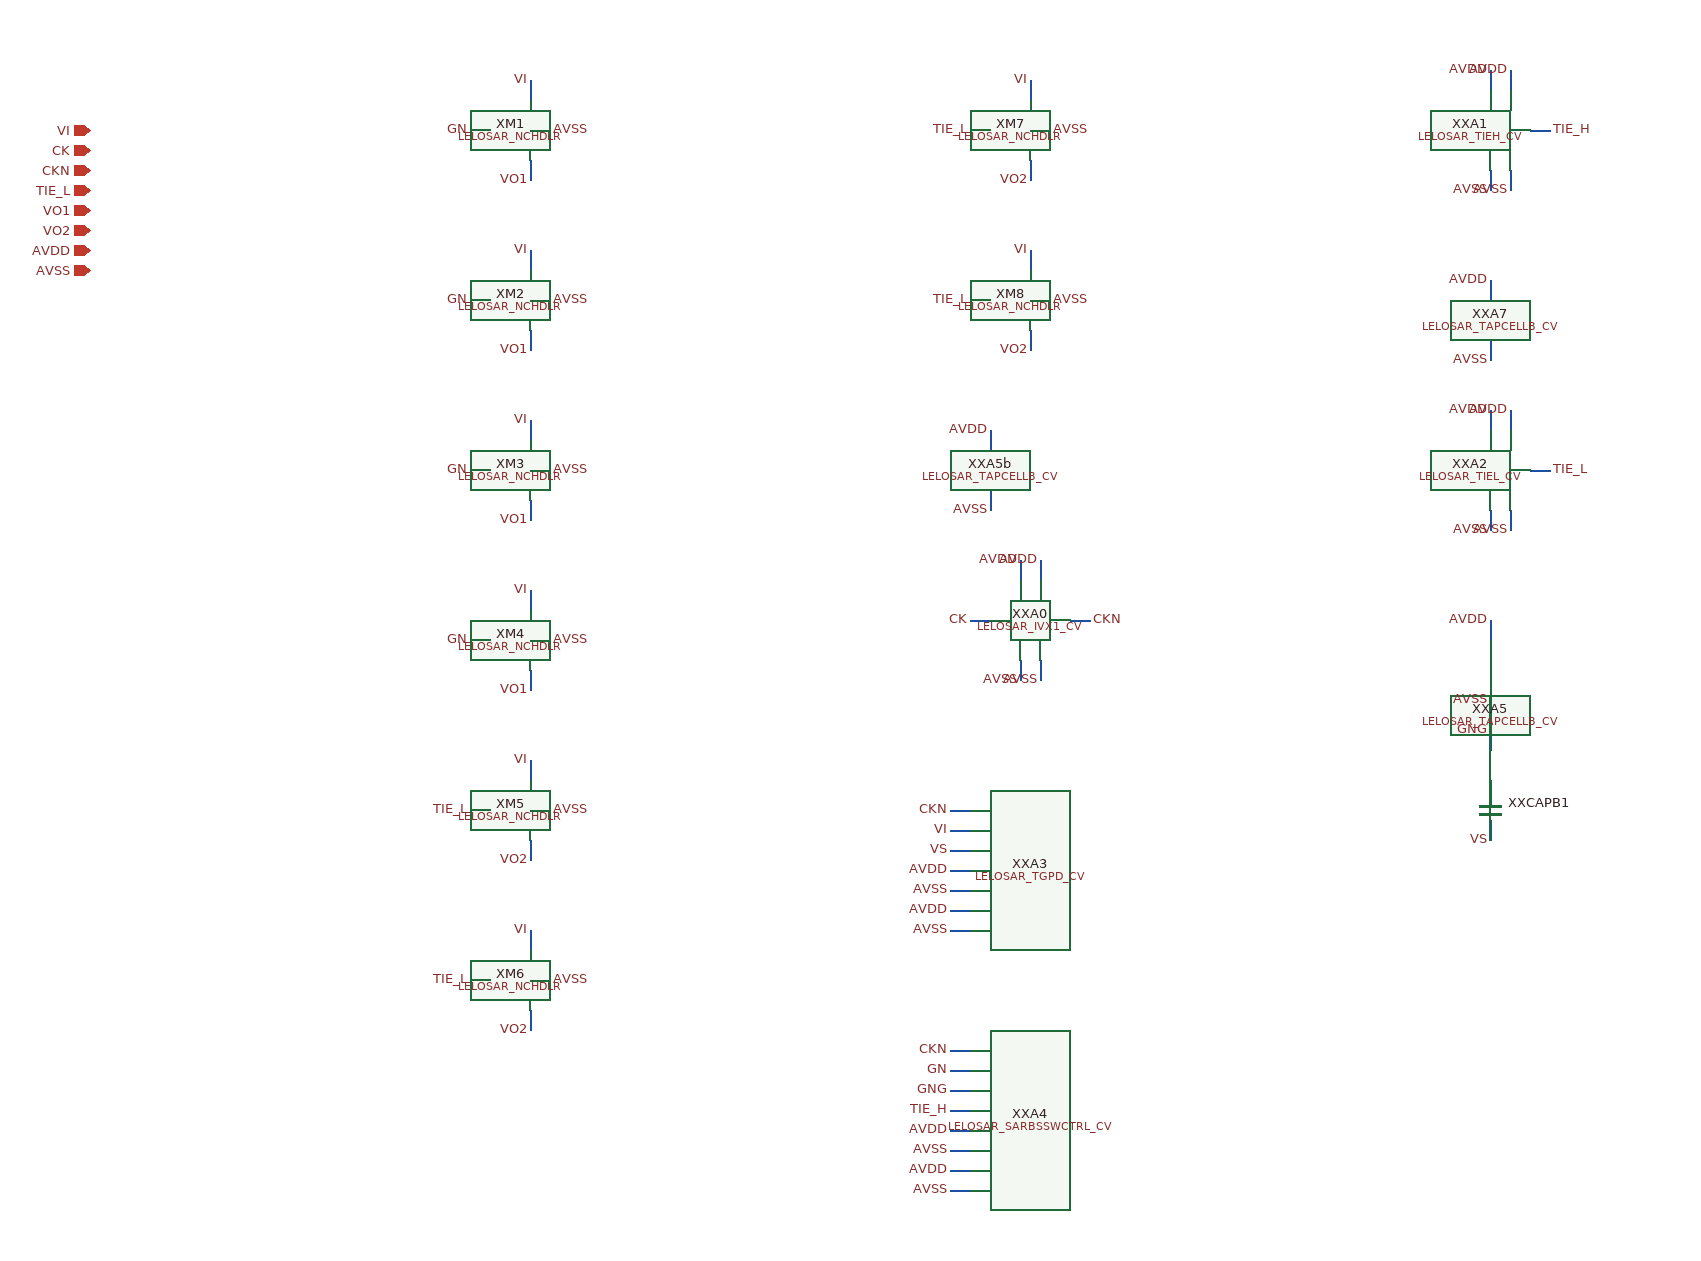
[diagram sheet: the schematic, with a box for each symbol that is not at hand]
v {xschem version=3.0.0 file_version=1.2 }
G {}
K {}
V {}
S {}
E {}
C {devices/iopin.sym} 0 0 0 0 {name=p0 lab=VI}
C {devices/iopin.sym} 0 20 0 0 {name=p1 lab=CK}
C {devices/iopin.sym} 0 40 0 0 {name=p2 lab=CKN}
C {devices/iopin.sym} 0 60 0 0 {name=p3 lab=TIE_L}
C {devices/iopin.sym} 0 80 0 0 {name=p4 lab=VO1}
C {devices/iopin.sym} 0 100 0 0 {name=p5 lab=VO2}
C {devices/iopin.sym} 0 120 0 0 {name=p6 lab=AVDD}
C {devices/iopin.sym} 0 140 0 0 {name=p7 lab=AVSS}
C {LELO_SAR9B_GF180MCUD/LELOSAR_NCHDLR.sym} 400 0 0 0 {name=XM1}
N 440.0 -50.0 440.0 -30.0 {lab=VI}
C {devices/lab_pin.sym} 440.0 -50.0 3 0 {name=l0 sig_type=std_logic lab=VI }
N 380.0 0.0 400.0 0.0 {lab=GN}
C {devices/lab_pin.sym} 380.0 0.0 0 0 {name=l1 sig_type=std_logic lab=GN }
N 440.0 50.0 440.0 30.0 {lab=VO1}
C {devices/lab_pin.sym} 440.0 50.0 1 0 {name=l2 sig_type=std_logic lab=VO1 }
N 460.0 0.0 440.0 0.0 {lab=AVSS}
C {devices/lab_pin.sym} 460.0 0.0 2 0 {name=l3 sig_type=std_logic lab=AVSS }
C {LELO_SAR9B_GF180MCUD/LELOSAR_NCHDLR.sym} 400 170 0 0 {name=XM2}
N 440.0 120.0 440.0 140.0 {lab=VI}
C {devices/lab_pin.sym} 440.0 120.0 3 0 {name=l4 sig_type=std_logic lab=VI }
N 380.0 170.0 400.0 170.0 {lab=GN}
C {devices/lab_pin.sym} 380.0 170.0 0 0 {name=l5 sig_type=std_logic lab=GN }
N 440.0 220.0 440.0 200.0 {lab=VO1}
C {devices/lab_pin.sym} 440.0 220.0 1 0 {name=l6 sig_type=std_logic lab=VO1 }
N 460.0 170.0 440.0 170.0 {lab=AVSS}
C {devices/lab_pin.sym} 460.0 170.0 2 0 {name=l7 sig_type=std_logic lab=AVSS }
C {LELO_SAR9B_GF180MCUD/LELOSAR_NCHDLR.sym} 400 340 0 0 {name=XM3}
N 440.0 290.0 440.0 310.0 {lab=VI}
C {devices/lab_pin.sym} 440.0 290.0 3 0 {name=l8 sig_type=std_logic lab=VI }
N 380.0 340.0 400.0 340.0 {lab=GN}
C {devices/lab_pin.sym} 380.0 340.0 0 0 {name=l9 sig_type=std_logic lab=GN }
N 440.0 390.0 440.0 370.0 {lab=VO1}
C {devices/lab_pin.sym} 440.0 390.0 1 0 {name=l10 sig_type=std_logic lab=VO1 }
N 460.0 340.0 440.0 340.0 {lab=AVSS}
C {devices/lab_pin.sym} 460.0 340.0 2 0 {name=l11 sig_type=std_logic lab=AVSS }
C {LELO_SAR9B_GF180MCUD/LELOSAR_NCHDLR.sym} 400 510 0 0 {name=XM4}
N 440.0 460.0 440.0 480.0 {lab=VI}
C {devices/lab_pin.sym} 440.0 460.0 3 0 {name=l12 sig_type=std_logic lab=VI }
N 380.0 510.0 400.0 510.0 {lab=GN}
C {devices/lab_pin.sym} 380.0 510.0 0 0 {name=l13 sig_type=std_logic lab=GN }
N 440.0 560.0 440.0 540.0 {lab=VO1}
C {devices/lab_pin.sym} 440.0 560.0 1 0 {name=l14 sig_type=std_logic lab=VO1 }
N 460.0 510.0 440.0 510.0 {lab=AVSS}
C {devices/lab_pin.sym} 460.0 510.0 2 0 {name=l15 sig_type=std_logic lab=AVSS }
C {LELO_SAR9B_GF180MCUD/LELOSAR_NCHDLR.sym} 400 680 0 0 {name=XM5}
N 440.0 630.0 440.0 650.0 {lab=VI}
C {devices/lab_pin.sym} 440.0 630.0 3 0 {name=l16 sig_type=std_logic lab=VI }
N 380.0 680.0 400.0 680.0 {lab=TIE_L}
C {devices/lab_pin.sym} 380.0 680.0 0 0 {name=l17 sig_type=std_logic lab=TIE_L }
N 440.0 730.0 440.0 710.0 {lab=VO2}
C {devices/lab_pin.sym} 440.0 730.0 1 0 {name=l18 sig_type=std_logic lab=VO2 }
N 460.0 680.0 440.0 680.0 {lab=AVSS}
C {devices/lab_pin.sym} 460.0 680.0 2 0 {name=l19 sig_type=std_logic lab=AVSS }
C {LELO_SAR9B_GF180MCUD/LELOSAR_NCHDLR.sym} 400 850 0 0 {name=XM6}
N 440.0 800.0 440.0 820.0 {lab=VI}
C {devices/lab_pin.sym} 440.0 800.0 3 0 {name=l20 sig_type=std_logic lab=VI }
N 380.0 850.0 400.0 850.0 {lab=TIE_L}
C {devices/lab_pin.sym} 380.0 850.0 0 0 {name=l21 sig_type=std_logic lab=TIE_L }
N 440.0 900.0 440.0 880.0 {lab=VO2}
C {devices/lab_pin.sym} 440.0 900.0 1 0 {name=l22 sig_type=std_logic lab=VO2 }
N 460.0 850.0 440.0 850.0 {lab=AVSS}
C {devices/lab_pin.sym} 460.0 850.0 2 0 {name=l23 sig_type=std_logic lab=AVSS }
C {LELO_SAR9B_GF180MCUD/LELOSAR_NCHDLR.sym} 900 0 0 0 {name=XM7}
N 940.0 -50.0 940.0 -30.0 {lab=VI}
C {devices/lab_pin.sym} 940.0 -50.0 3 0 {name=l24 sig_type=std_logic lab=VI }
N 880.0 0.0 900.0 0.0 {lab=TIE_L}
C {devices/lab_pin.sym} 880.0 0.0 0 0 {name=l25 sig_type=std_logic lab=TIE_L }
N 940.0 50.0 940.0 30.0 {lab=VO2}
C {devices/lab_pin.sym} 940.0 50.0 1 0 {name=l26 sig_type=std_logic lab=VO2 }
N 960.0 0.0 940.0 0.0 {lab=AVSS}
C {devices/lab_pin.sym} 960.0 0.0 2 0 {name=l27 sig_type=std_logic lab=AVSS }
C {LELO_SAR9B_GF180MCUD/LELOSAR_NCHDLR.sym} 900 170 0 0 {name=XM8}
N 940.0 120.0 940.0 140.0 {lab=VI}
C {devices/lab_pin.sym} 940.0 120.0 3 0 {name=l28 sig_type=std_logic lab=VI }
N 880.0 170.0 900.0 170.0 {lab=TIE_L}
C {devices/lab_pin.sym} 880.0 170.0 0 0 {name=l29 sig_type=std_logic lab=TIE_L }
N 940.0 220.0 940.0 200.0 {lab=VO2}
C {devices/lab_pin.sym} 940.0 220.0 1 0 {name=l30 sig_type=std_logic lab=VO2 }
N 960.0 170.0 940.0 170.0 {lab=AVSS}
C {devices/lab_pin.sym} 960.0 170.0 2 0 {name=l31 sig_type=std_logic lab=AVSS }
C {LELO_SAR9B_GF180MCUD/LELOSAR_TAPCELLB_CV.sym} 900 340 0 0 {name=XXA5b}
N 900.0 300.0 900.0 320.0 {lab=AVDD}
C {devices/lab_pin.sym} 900.0 300.0 3 0 {name=l32 sig_type=std_logic lab=AVDD }
N 900.0 380.0 900.0 360.0 {lab=AVSS}
C {devices/lab_pin.sym} 900.0 380.0 1 0 {name=l33 sig_type=std_logic lab=AVSS }
C {LELO_SAR9B_GF180MCUD/LELOSAR_IVX1_CV.sym} 900 490 0 0 {name=XXA0}
N 880.0 490.0 900.0 490.0 {lab=CK}
C {devices/lab_pin.sym} 880.0 490.0 0 0 {name=l34 sig_type=std_logic lab=CK }
N 1000.0 490.0 980.0 490.0 {lab=CKN}
C {devices/lab_pin.sym} 1000.0 490.0 2 0 {name=l35 sig_type=std_logic lab=CKN }
N 950.0 430.0 950.0 450.0 {lab=AVDD}
C {devices/lab_pin.sym} 950.0 430.0 3 0 {name=l36 sig_type=std_logic lab=AVDD }
N 950.0 550.0 950.0 530.0 {lab=AVSS}
C {devices/lab_pin.sym} 950.0 550.0 1 0 {name=l37 sig_type=std_logic lab=AVSS }
N 930.0 430.0 930.0 450.0 {lab=AVDD}
C {devices/lab_pin.sym} 930.0 430.0 3 0 {name=l38 sig_type=std_logic lab=AVDD }
N 930.0 550.0 930.0 530.0 {lab=AVSS}
C {devices/lab_pin.sym} 930.0 550.0 1 0 {name=l39 sig_type=std_logic lab=AVSS }
C {LELO_SAR9B_GF180MCUD/LELOSAR_TGPD_CV.sym} 900 680 0 0 {name=XXA3}
N 860.0 680.0 880.0 680.0 {lab=CKN}
C {devices/lab_pin.sym} 860.0 680.0 0 0 {name=l40 sig_type=std_logic lab=CKN }
N 860.0 700.0 880.0 700.0 {lab=VI}
C {devices/lab_pin.sym} 860.0 700.0 0 0 {name=l41 sig_type=std_logic lab=VI }
N 860.0 720.0 880.0 720.0 {lab=VS}
C {devices/lab_pin.sym} 860.0 720.0 0 0 {name=l42 sig_type=std_logic lab=VS }
N 860.0 740.0 880.0 740.0 {lab=AVDD}
C {devices/lab_pin.sym} 860.0 740.0 0 0 {name=l43 sig_type=std_logic lab=AVDD }
N 860.0 760.0 880.0 760.0 {lab=AVSS}
C {devices/lab_pin.sym} 860.0 760.0 0 0 {name=l44 sig_type=std_logic lab=AVSS }
N 860.0 780.0 880.0 780.0 {lab=AVDD}
C {devices/lab_pin.sym} 860.0 780.0 0 0 {name=l45 sig_type=std_logic lab=AVDD }
N 860.0 800.0 880.0 800.0 {lab=AVSS}
C {devices/lab_pin.sym} 860.0 800.0 0 0 {name=l46 sig_type=std_logic lab=AVSS }
C {LELO_SAR9B_GF180MCUD/LELOSAR_SARBSSWCTRL_CV.sym} 900 920 0 0 {name=XXA4}
N 860.0 920.0 880.0 920.0 {lab=CKN}
C {devices/lab_pin.sym} 860.0 920.0 0 0 {name=l47 sig_type=std_logic lab=CKN }
N 860.0 940.0 880.0 940.0 {lab=GN}
C {devices/lab_pin.sym} 860.0 940.0 0 0 {name=l48 sig_type=std_logic lab=GN }
N 860.0 960.0 880.0 960.0 {lab=GNG}
C {devices/lab_pin.sym} 860.0 960.0 0 0 {name=l49 sig_type=std_logic lab=GNG }
N 860.0 980.0 880.0 980.0 {lab=TIE_H}
C {devices/lab_pin.sym} 860.0 980.0 0 0 {name=l50 sig_type=std_logic lab=TIE_H }
N 860.0 1000.0 880.0 1000.0 {lab=AVDD}
C {devices/lab_pin.sym} 860.0 1000.0 0 0 {name=l51 sig_type=std_logic lab=AVDD }
N 860.0 1020.0 880.0 1020.0 {lab=AVSS}
C {devices/lab_pin.sym} 860.0 1020.0 0 0 {name=l52 sig_type=std_logic lab=AVSS }
N 860.0 1040.0 880.0 1040.0 {lab=AVDD}
C {devices/lab_pin.sym} 860.0 1040.0 0 0 {name=l53 sig_type=std_logic lab=AVDD }
N 860.0 1060.0 880.0 1060.0 {lab=AVSS}
C {devices/lab_pin.sym} 860.0 1060.0 0 0 {name=l54 sig_type=std_logic lab=AVSS }
C {LELO_SAR9B_GF180MCUD/LELOSAR_TIEH_CV.sym} 1400 0 0 0 {name=XXA1}
N 1460.0 0.0 1440.0 0.0 {lab=TIE_H}
C {devices/lab_pin.sym} 1460.0 0.0 2 0 {name=l55 sig_type=std_logic lab=TIE_H }
N 1420.0 -60.0 1420.0 -40.0 {lab=AVDD}
C {devices/lab_pin.sym} 1420.0 -60.0 3 0 {name=l56 sig_type=std_logic lab=AVDD }
N 1420.0 60.0 1420.0 40.0 {lab=AVSS}
C {devices/lab_pin.sym} 1420.0 60.0 1 0 {name=l57 sig_type=std_logic lab=AVSS }
N 1400.0 -60.0 1400.0 -40.0 {lab=AVDD}
C {devices/lab_pin.sym} 1400.0 -60.0 3 0 {name=l58 sig_type=std_logic lab=AVDD }
N 1400.0 60.0 1400.0 40.0 {lab=AVSS}
C {devices/lab_pin.sym} 1400.0 60.0 1 0 {name=l59 sig_type=std_logic lab=AVSS }
C {LELO_SAR9B_GF180MCUD/LELOSAR_TAPCELLB_CV.sym} 1400 190 0 0 {name=XXA7}
N 1400.0 150.0 1400.0 170.0 {lab=AVDD}
C {devices/lab_pin.sym} 1400.0 150.0 3 0 {name=l60 sig_type=std_logic lab=AVDD }
N 1400.0 230.0 1400.0 210.0 {lab=AVSS}
C {devices/lab_pin.sym} 1400.0 230.0 1 0 {name=l61 sig_type=std_logic lab=AVSS }
C {LELO_SAR9B_GF180MCUD/LELOSAR_TIEL_CV.sym} 1400 340 0 0 {name=XXA2}
N 1460.0 340.0 1440.0 340.0 {lab=TIE_L}
C {devices/lab_pin.sym} 1460.0 340.0 2 0 {name=l62 sig_type=std_logic lab=TIE_L }
N 1420.0 280.0 1420.0 300.0 {lab=AVDD}
C {devices/lab_pin.sym} 1420.0 280.0 3 0 {name=l63 sig_type=std_logic lab=AVDD }
N 1420.0 400.0 1420.0 380.0 {lab=AVSS}
C {devices/lab_pin.sym} 1420.0 400.0 1 0 {name=l64 sig_type=std_logic lab=AVSS }
N 1400.0 280.0 1400.0 300.0 {lab=AVDD}
C {devices/lab_pin.sym} 1400.0 280.0 3 0 {name=l65 sig_type=std_logic lab=AVDD }
N 1400.0 400.0 1400.0 380.0 {lab=AVSS}
C {devices/lab_pin.sym} 1400.0 400.0 1 0 {name=l66 sig_type=std_logic lab=AVSS }
C {LELO_SAR9B_GF180MCUD/LELOSAR_TAPCELLB_CV.sym} 1400 530 0 0 {name=XXA5}
N 1400.0 490.0 1400.0 510.0 {lab=AVDD}
C {devices/lab_pin.sym} 1400.0 490.0 3 0 {name=l67 sig_type=std_logic lab=AVDD }
N 1400.0 570.0 1400.0 550.0 {lab=AVSS}
C {devices/lab_pin.sym} 1400.0 570.0 1 0 {name=l68 sig_type=std_logic lab=AVSS }
C {LELO_SAR9B_GF180MCUD/LELOSAR_CAP_BSSW5_CV.sym} 1400 680 0 0 {name=XXCAPB1}
N 1400.0 600.0 1400.0 620.0 {lab=GNG}
C {devices/lab_pin.sym} 1400.0 600.0 3 0 {name=l69 sig_type=std_logic lab=GNG }
N 1400.0 710.0 1400.0 690.0 {lab=VS}
C {devices/lab_pin.sym} 1400.0 710.0 1 0 {name=l70 sig_type=std_logic lab=VS }
